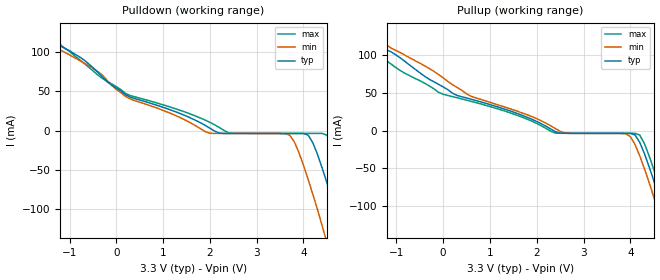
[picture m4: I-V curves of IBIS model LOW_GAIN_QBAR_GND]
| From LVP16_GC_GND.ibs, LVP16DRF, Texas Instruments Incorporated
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|   Q_bar Output Model
[Model]   LOW_GAIN_QBAR_GND
Model_type   Output_ECL
| Signals   Q/
Vmeas = 2.0V   |Reference voltage for timing measurements
Cref = 0pF   |Timing specification test load capacitance value
|Rref = 50
| variable   typ   min   max
C_comp   0.6pF   0.4pF   0.7pF
|   typ   min   max
[Temperature Range]   25   -40   85
[Voltage range]   3.3V   3.0V   3.6V
[Pulldown]
|Voltage I(typ)   I(min)   I(max)
| Note that the[Pulldown]voltage table for (P)ECL is referenced
| to Vcc and is calculated using Vtable=Vcc - Vmeasured.
-3.3V     261mA      264mA      257mA
-1.8V     129mA      124mA      134mA
-500mV    80.4mA     79.5mA     76.3mA
200mV     45.7mA     43.5mA     47.3mA
2V        3.03mA     -3.43mA    10.4mA
2.4V      -3.71mA    -3.77mA    -2.99mA
3.7V      -3.75mA    -5.66mA    -3.64mA
4.1V      -5.83mA    -62.5mA    -3.65mA
4.5V      -66.6mA    -143mA     -5.94mA
4.8V      -127mA     -208mA     -51.6mA
5.2V      -214mA     -300mA     -132mA
6.6V      -556mA     -653mA     -461mA
[Pullup]
|Voltage   I(typ)   I(min)   I(max)
| Note that the[Pullup]voltage table is referenced to Vcc
| and is calculated using Vtable=Vcc - Vmeasured.
-3.3V     260mA      298mA      226mA
-2.3V     161mA      199mA      140mA
-1.7V     124mA      143mA      116mA
-100mV    61.4mA     74.4mA     50.8mA
600mV     41.5mA     45.4mA     38.7mA
2.4V      -1.58mA    2.54mA     -3.42mA
3.9V      -3.75mA    -4.27mA    -3.65mA
4.2V      -15.6mA    -33.5mA    -5.94mA
4.7V      -106mA     -129mA     -90.8mA
4.9V      -148mA     -171mA     -132mA
5V        -170mA     -193mA     -154mA
6.6V      -556mA     -581mA     -538mA
[Ramp]
|   typ   min   max
dV/dt_r   0.159/198ps   0.158/193ps   0.159/181ps
dV/dt_f   0.159/177ps   0.158/193ps   0.159/155ps
